One B-rep face of a CAD part: STEP entity #1398.
In plain terms, the planar face has unit normal (1, 0, 0).
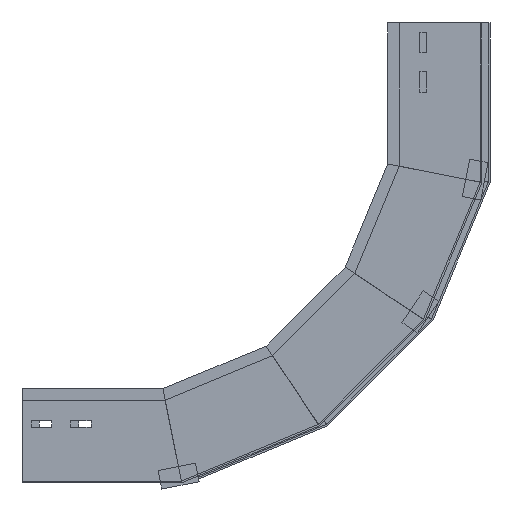
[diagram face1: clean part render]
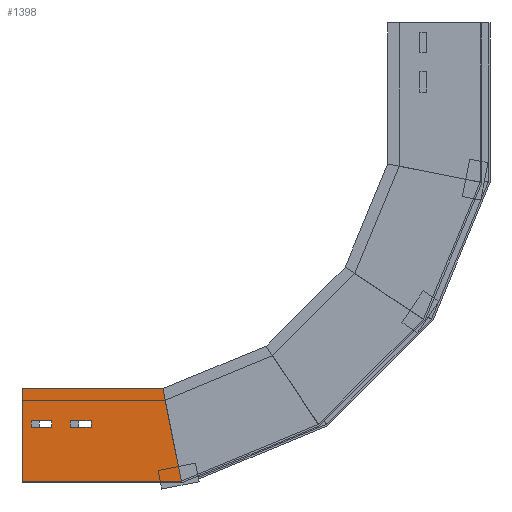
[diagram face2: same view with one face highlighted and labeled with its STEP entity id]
Its self-contained STEP definition (entity closure, numbers rounded to 3 decimals):
#19 = VERTEX_POINT ( 'NONE', #137 ) ;
#77 = VECTOR ( 'NONE', #324, 1000. ) ;
#99 = CARTESIAN_POINT ( 'NONE',  ( 0., 0., 0. ) ) ;
#113 = CARTESIAN_POINT ( 'NONE',  ( 0., 66., -51.505 ) ) ;
#137 = CARTESIAN_POINT ( 'NONE',  ( 0., 100., -149.709 ) ) ;
#148 = EDGE_LOOP ( 'NONE', ( #616, #1347, #859, #439 ) ) ;
#159 = CARTESIAN_POINT ( 'NONE',  ( 0., 66., -31.835 ) ) ;
#184 = DIRECTION ( 'NONE',  ( 0., -0.981, -0.195 ) ) ;
#186 = VERTEX_POINT ( 'NONE', #1275 ) ;
#211 = PLANE ( 'NONE',  #410 ) ;
#284 = CARTESIAN_POINT ( 'NONE',  ( 0., 66., -73.505 ) ) ;
#311 = CARTESIAN_POINT ( 'NONE',  ( 0., 100., 0. ) ) ;
#324 = DIRECTION ( 'NONE',  ( 0., -1., 0. ) ) ;
#328 = EDGE_CURVE ( 'NONE', #466, #1351, #1565, .T. ) ;
#410 = AXIS2_PLACEMENT_3D ( 'NONE', #651, #1825, #953 ) ;
#427 = ORIENTED_EDGE ( 'NONE', *, *, #914, .T. ) ;
#435 = CARTESIAN_POINT ( 'NONE',  ( 0., 66., -73.505 ) ) ;
#439 = ORIENTED_EDGE ( 'NONE', *, *, #1202, .F. ) ;
#466 = VERTEX_POINT ( 'NONE', #1588 ) ;
#480 = VECTOR ( 'NONE', #1487, 1000. ) ;
#539 = LINE ( 'NONE', #1122, #1113 ) ;
#553 = CARTESIAN_POINT ( 'NONE',  ( 0., 0., 0. ) ) ;
#572 = DIRECTION ( 'NONE',  ( 0., 0., -1. ) ) ;
#601 = VECTOR ( 'NONE', #1413, 1000. ) ;
#606 = EDGE_LOOP ( 'NONE', ( #427, #1871, #1803, #1542 ) ) ;
#616 = ORIENTED_EDGE ( 'NONE', *, *, #1580, .F. ) ;
#637 = VERTEX_POINT ( 'NONE', #1575 ) ;
#646 = DIRECTION ( 'NONE',  ( 0., 0., -1. ) ) ;
#651 = CARTESIAN_POINT ( 'NONE',  ( 0., 0., 0. ) ) ;
#664 = VERTEX_POINT ( 'NONE', #113 ) ;
#667 = DIRECTION ( 'NONE',  ( 0., 1., 0. ) ) ;
#669 = CARTESIAN_POINT ( 'NONE',  ( 0., 59., -9.835 ) ) ;
#700 = VERTEX_POINT ( 'NONE', #284 ) ;
#704 = LINE ( 'NONE', #99, #1117 ) ;
#759 = LINE ( 'NONE', #435, #77 ) ;
#774 = LINE ( 'NONE', #1757, #1878 ) ;
#833 = CARTESIAN_POINT ( 'NONE',  ( 0., 59., -51.505 ) ) ;
#834 = EDGE_CURVE ( 'NONE', #700, #466, #759, .T. ) ;
#844 = VECTOR ( 'NONE', #1199, 1000. ) ;
#859 = ORIENTED_EDGE ( 'NONE', *, *, #1809, .T. ) ;
#895 = VERTEX_POINT ( 'NONE', #1843 ) ;
#897 = LINE ( 'NONE', #1459, #844 ) ;
#909 = LINE ( 'NONE', #159, #480 ) ;
#914 = EDGE_CURVE ( 'NONE', #1666, #186, #1394, .T. ) ;
#918 = DIRECTION ( 'NONE',  ( 0., 0., -1. ) ) ;
#937 = CARTESIAN_POINT ( 'NONE',  ( 0., 59., -51.505 ) ) ;
#940 = CARTESIAN_POINT ( 'NONE',  ( 0., 66., -9.835 ) ) ;
#945 = VERTEX_POINT ( 'NONE', #1385 ) ;
#951 = EDGE_CURVE ( 'NONE', #1351, #664, #1091, .T. ) ;
#953 = DIRECTION ( 'NONE',  ( 0., 0., 1. ) ) ;
#964 = FACE_OUTER_BOUND ( 'NONE', #148, .T. ) ;
#978 = EDGE_CURVE ( 'NONE', #664, #700, #539, .T. ) ;
#985 = DIRECTION ( 'NONE',  ( 0., 0., 1. ) ) ;
#994 = VECTOR ( 'NONE', #1555, 1000. ) ;
#1001 = ORIENTED_EDGE ( 'NONE', *, *, #951, .T. ) ;
#1016 = DIRECTION ( 'NONE',  ( 0., 0., -1. ) ) ;
#1023 = VECTOR ( 'NONE', #918, 1000. ) ;
#1091 = LINE ( 'NONE', #1659, #994 ) ;
#1113 = VECTOR ( 'NONE', #646, 1000. ) ;
#1117 = VECTOR ( 'NONE', #572, 1000. ) ;
#1122 = CARTESIAN_POINT ( 'NONE',  ( 0., 66., -51.505 ) ) ;
#1130 = LINE ( 'NONE', #1706, #1298 ) ;
#1134 = ORIENTED_EDGE ( 'NONE', *, *, #328, .T. ) ;
#1155 = EDGE_LOOP ( 'NONE', ( #1001, #1574, #1169, #1134 ) ) ;
#1169 = ORIENTED_EDGE ( 'NONE', *, *, #834, .T. ) ;
#1171 = EDGE_CURVE ( 'NONE', #895, #1666, #1130, .T. ) ;
#1174 = CARTESIAN_POINT ( 'NONE',  ( 0., 66., -9.835 ) ) ;
#1181 = EDGE_CURVE ( 'NONE', #186, #945, #1623, .T. ) ;
#1199 = DIRECTION ( 'NONE',  ( 0., 1., 0. ) ) ;
#1202 = EDGE_CURVE ( 'NONE', #19, #1634, #774, .T. ) ;
#1275 = CARTESIAN_POINT ( 'NONE',  ( 0., 66., -9.835 ) ) ;
#1298 = VECTOR ( 'NONE', #985, 1000. ) ;
#1347 = ORIENTED_EDGE ( 'NONE', *, *, #1607, .F. ) ;
#1351 = VERTEX_POINT ( 'NONE', #937 ) ;
#1385 = CARTESIAN_POINT ( 'NONE',  ( 0., 66., -31.835 ) ) ;
#1394 = LINE ( 'NONE', #940, #1508 ) ;
#1398 = ADVANCED_FACE ( 'NONE', ( #1682, #964, #1814 ), #211, .F. ) ;
#1413 = DIRECTION ( 'NONE',  ( 0., 0., 1. ) ) ;
#1459 = CARTESIAN_POINT ( 'NONE',  ( 0., 0., 0. ) ) ;
#1487 = DIRECTION ( 'NONE',  ( 0., -1., 0. ) ) ;
#1508 = VECTOR ( 'NONE', #667, 1000. ) ;
#1542 = ORIENTED_EDGE ( 'NONE', *, *, #1171, .T. ) ;
#1551 = VERTEX_POINT ( 'NONE', #553 ) ;
#1555 = DIRECTION ( 'NONE',  ( 0., 1., 0. ) ) ;
#1565 = LINE ( 'NONE', #833, #601 ) ;
#1574 = ORIENTED_EDGE ( 'NONE', *, *, #978, .T. ) ;
#1575 = CARTESIAN_POINT ( 'NONE',  ( 0., 100., 0. ) ) ;
#1580 = EDGE_CURVE ( 'NONE', #637, #19, #1620, .T. ) ;
#1588 = CARTESIAN_POINT ( 'NONE',  ( 0., 59., -73.505 ) ) ;
#1607 = EDGE_CURVE ( 'NONE', #1551, #637, #897, .T. ) ;
#1620 = LINE ( 'NONE', #311, #1725 ) ;
#1623 = LINE ( 'NONE', #1174, #1023 ) ;
#1629 = CARTESIAN_POINT ( 'NONE',  ( 0., 0., -169.6 ) ) ;
#1634 = VERTEX_POINT ( 'NONE', #1629 ) ;
#1637 = EDGE_CURVE ( 'NONE', #945, #895, #909, .T. ) ;
#1659 = CARTESIAN_POINT ( 'NONE',  ( 0., 66., -51.505 ) ) ;
#1666 = VERTEX_POINT ( 'NONE', #669 ) ;
#1682 = FACE_BOUND ( 'NONE', #1155, .T. ) ;
#1706 = CARTESIAN_POINT ( 'NONE',  ( 0., 59., -9.835 ) ) ;
#1725 = VECTOR ( 'NONE', #1016, 1000. ) ;
#1757 = CARTESIAN_POINT ( 'NONE',  ( 0., 32.452, -163.145 ) ) ;
#1803 = ORIENTED_EDGE ( 'NONE', *, *, #1637, .T. ) ;
#1809 = EDGE_CURVE ( 'NONE', #1551, #1634, #704, .T. ) ;
#1814 = FACE_BOUND ( 'NONE', #606, .T. ) ;
#1825 = DIRECTION ( 'NONE',  ( -1., 0., 0. ) ) ;
#1843 = CARTESIAN_POINT ( 'NONE',  ( 0., 59., -31.835 ) ) ;
#1871 = ORIENTED_EDGE ( 'NONE', *, *, #1181, .T. ) ;
#1878 = VECTOR ( 'NONE', #184, 1000. ) ;
